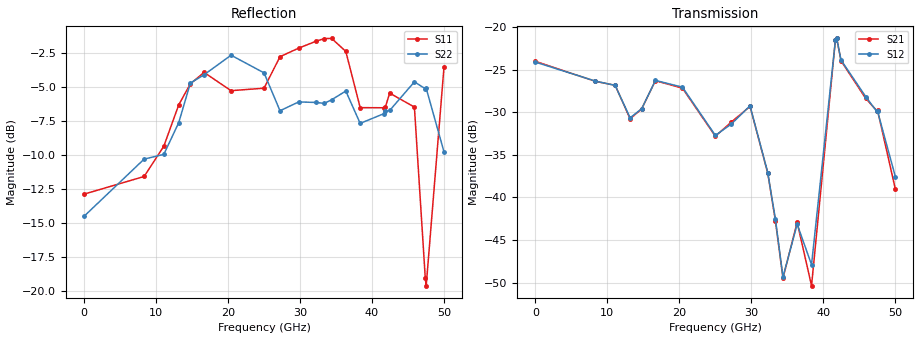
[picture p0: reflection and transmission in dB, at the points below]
!Keysight Technologies,N5245B,MY58422270,A.16.20.02
!Date: Thursday, March 05, 2026 01:30:45
!Correction: S11(C  2-Port  )
!S21(C  2-Port  )
!S12(C  2-Port  )
!S22(C  2-Port  )
!S2P File: Measurements: S11, S21, S12, S22:
# Hz S  dB  R 50
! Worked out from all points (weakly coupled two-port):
!   3201 points, 10 MHz to 50 GHz, reference 50 ohm
!   highest |S21| = -21.32 dB at 41.86 GHz (marker M1); lowest = -50.4 dB at 38.36 GHz (marker M2)
!   lowest |S11| = -19.6 dB at 47.53 GHz (marker M3), VSWR 1.23, Z = 45.8 + j9.12 ohm
!   |S11| at or under -10 dB: start of sweep to 10.12 GHz; 11.35 GHz to 11.93 GHz (570.9 MHz wide, 4.9 % of centre); 46.67 GHz to 48.28 GHz (1.606 GHz wide, 3.38 % of centre)
!   |S22| runs from -18.3 to -2.6 dB; largest |S21 - S12| = 0.0025
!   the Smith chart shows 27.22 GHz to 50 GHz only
!   S11 on the Smith chart (normalised r, x): 27.22 GHz: 0.18, +0.36; 32.28 GHz: 0.42, +1.85; 36.36 GHz: 2.40, -3.37; 42.45 GHz: 0.99, -1.26; 47.41 GHz: 0.84, +0.13; 50 GHz: 0.62, -1.36
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1e7  -12.87 -4.2  -24.01 4.9  -24.10 4.9  -14.50 38.4
8.352081e9  -11.57 174.9  -26.36 28.0  -26.33 28.1  -10.29 -176.4
1.108591e10  -9.34 109.2  -26.82 -73.1  -26.84 -73.3  -9.94 83.3
1.316362e10  -6.29 64.2  -30.76 -129.0  -30.64 -128.9  -7.60 -24.3
1.477267e10  -4.75 12.8  -29.59 -150.2  -29.57 -150.0  -4.69 -91.2
1.667854e10  -3.91 -43.8  -26.28 158.8  -26.25 158.9  -4.08 -141.0
2.042779e10  -5.25 -121.8  -27.16 39.4  -27.04 39.6  -2.64 155.0
2.5005e10  -5.07 180.0  -32.81 -65.4  -32.71 -65.8  -3.94 71.8
2.722331e10  -2.75 139.0  -31.14 -115.1  -31.37 -114.6  -6.73 31.8
2.981654e10  -2.12 94.0  -29.31 159.2  -29.23 158.5  -6.08 -28.3
3.228479e10  -1.60 55.0  -37.16 47.9  -37.08 46.9  -6.12 -102.9
3.334708e10  -1.42 36.1  -42.77 3.4  -42.57 3.2  -6.19 -126.3
3.439375e10  -1.40 17.4  -49.49 -92.3  -49.34 -92.3  -5.92 -148.4
3.63621e10  -2.36 -22.7  -42.91 115.8  -43.14 110.8  -5.28 174.3
3.83617e10  -6.50 -22.3  -50.36 -96.7  -47.89 -73.6  -7.66 141.7
4.167354e10  -6.51 -52.6  -21.52 -54.6  -21.56 -54.8  -6.94 115.6
4.1861e10  -6.45 -52.5  -21.32 -71.9  -21.31 -72.7  -6.78 113.7
4.245463e10  -5.43 -57.9  -23.95 -114.8  -23.86 -115.2  -6.71 110.3
4.589145e10  -6.46 -117.0  -28.37 51.0  -28.16 50.3  -4.60 63.0
4.740677e10  -19.08 138.1  -29.79 -2.0  -29.88 -2.5  -5.11 43.4
4.753174e10  -19.61 109.5  -29.77 -3.8  -29.88 -4.5  -5.08 42.0
5e10  -3.52 -65.8  -39.01 -128.8  -37.54 -135.7  -9.75 3.6
